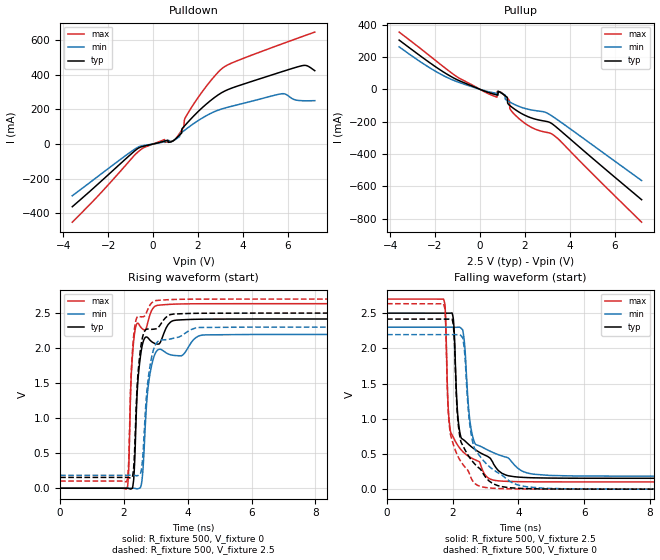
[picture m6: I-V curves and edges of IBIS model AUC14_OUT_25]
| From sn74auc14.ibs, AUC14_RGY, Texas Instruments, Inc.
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[Model]   AUC14_OUT_25
Model_type  Output
Vref =   0
Rref =   500
Cref =   30p
Vmeas =   1.25
| variable   typ   min   max
C_comp   8.27pF   2.05pF   24.54pF
| C_pullup   9.62pF   2.22pF   24.54pF
| C_pulldown   6.92pF   2.05pF   16.12pF
[Temperature Range]   40   100   -40
| Ambient temperature   25   85   -40
[Voltage range]   2.5   2.3   2.7
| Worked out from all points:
|   slope of the pulldown table from 0 to 0.375 V, typ, clamps not added: 30.7 ohm
|   slope of the pullup table from 0 to 0.375 V, typ, clamps not added: 19.1 ohm
|   rising waveform, R_fixture 500, V_fixture 0: 20-80 % time 188ps typ, 251ps min, 141ps max; typ from 0 V to 2.42 V
|   falling waveform, R_fixture 500, V_fixture 2.5: 20-80 % time 450ps typ, 462ps min, 354ps max; typ from 2.5 V to 0.155 V
|   rising waveform, R_fixture 500, V_fixture 2.5: 20-80 % time 191ps typ, 259ps min, 142ps max; typ from 0.154 V to 2.5 V
|   falling waveform, R_fixture 500, V_fixture 0: 20-80 % time 401ps typ, 485ps min, 301ps max; typ from 2.42 V to 0 V
[Pulldown]
| AUC14_OUT_25
|   Voltage   I(typ)   I(min)   I(max)
-3.6V     -363.3mA   -299.7mA   -452.8mA
-560mV    -17.97mA   -12.29mA   -33.51mA
510mV     17.07mA    12.84mA    25.87mA
975mV     26.82mA    25.47mA    25.82mA
1.27V     63.12mA    66.67mA    79.37mA
1.37V     100.7mA    76.6mA     99.34mA
1.42V     107.9mA    81.53mA    148.5mA
1.84V     166.6mA    121.2mA    238mA
3.1V      300.6mA    204.7mA    440.5mA
5.74V     418.9mA    291.2mA    579.9mA
6.745V    455.6mA    250.5mA    627.2mA
7.2V      424.9mA    251.1mA    648.3mA
[Pullup]
| AUC14_OUT_25
|   Voltage   I(typ)   I(min)   I(max)
-3.6V     305mA      263.2mA    354.5mA
-960mV    55.76mA    44.28mA    72.07mA
730mV     -33.82mA   -24.42mA   -47.21mA
760mV     -34.84mA   -25.13mA   -47.16mA
770mV     -35.18mA   -25.36mA   -13.25mA
980mV     -25.02mA   -24.81mA   -22.86mA
1.215V    -49.49mA   -69.56mA   -54.81mA
1.3V      -96.78mA   -76.45mA   -67.02mA
1.34V     -101.5mA   -79.57mA   -121.6mA
1.66V     -133.9mA   -101.4mA   -171.6mA
3.46V     -241mA     -189.3mA   -303.8mA
7.2V      -683.6mA   -565.1mA   -822.8mA
[Ramp]
| AUC14_OUT_25
| variable   typ   min   max
dV/dt_r   1.46/1.88E-10   1.32/2.51E-10   1.59/1.43E-10
dV/dt_f   1.41/4.50E-10   1.27/4.63E-10   1.56/3.59E-10
R_load = 500
[Rising Waveform]
| AUC14_OUT_25
R_fixture =   500
C_fixture =   0
L_fixture =   0
V_fixture =   0
V_fixture_min = 0
V_fixture_max = 0
|   Time   V(typ)   V(min)   V(max)
0s        13.01nV    39.01nV    2.017nV
2.085ns   260.6uV    462.9uV    -4.945mV
2.145ns   -3.048mV   695.5uV    232.7mV
2.235ns   -7.736mV   886.8uV    1.668V
2.345ns   486.5mV    -2.513mV   2.25V
2.43ns    1.488V     -7.472mV   2.356V
2.57ns    2.032V     134.6mV    2.279V
2.76ns    2.143V     1.456V     2.388V
3.045ns   2.057V     1.968V     2.61V
22ns      2.416V     2.195V     2.634V
[Falling Waveform]
| AUC14_OUT_25
R_fixture =   500
C_fixture =   0
L_fixture =   0
V_fixture =   2.5
V_fixture_min = 2.3
V_fixture_max = 2.7
|   Time   V(typ)   V(min)   V(max)
0s        2.5V       2.3V       2.7V
1.72ns    2.5V       2.3V       2.699V
1.865ns   2.499V     2.3V       1.135V
1.94ns    2.5V       2.3V       806.6mV
2.025ns   2.384V     2.299V     729.3mV
2.14ns    1.135V     2.299V     632mV
2.245ns   746.1mV    2.29V      564.7mV
2.615ns   585.3mV    733.4mV    431.8mV
3.215ns   385.9mV    523mV      131.6mV
22ns      154.5mV    184.4mV    102.7mV
[Rising Waveform]
| AUC14_OUT_25
R_fixture =   500
C_fixture =   0
L_fixture =   0
V_fixture =   2.5
V_fixture_min = 2.3
V_fixture_max = 2.7
|   Time   V(typ)   V(min)   V(max)
0s        154.5mV    184.4mV    102.6mV
2.08ns    154.8mV    184.7mV    94.72mV
2.145ns   151.9mV    185mV      348.9mV
2.265ns   161.2mV    184.9mV    1.946V
2.345ns   667mV      182.3mV    2.328V
2.425ns   1.541V     179.7mV    2.449V
2.555ns   2.095V     289.5mV    2.446V
2.74ns    2.272V     1.488V     2.545V
2.985ns   2.274V     2.046V     2.677V
22ns      2.5V       2.3V       2.7V
[Falling Waveform]
| AUC14_OUT_25
R_fixture =   500
C_fixture =   0
L_fixture =   0
V_fixture =   0
V_fixture_min = 0
V_fixture_max = 0
|   Time   V(typ)   V(min)   V(max)
0s        2.416V     2.195V     2.634V
1.72ns    2.416V     2.195V     2.632V
1.93ns    2.414V     2.195V     780.2mV
2.025ns   2.295V     2.195V     626.3mV
2.13ns    1.151V     2.194V     494.6mV
2.235ns   701.1mV    2.186V     401.9mV
2.565ns   416.2mV    770.5mV    152.3mV
2.875ns   263.4mV    439.3mV    34.57mV
4.75ns    3.284mV    13.71mV    801.9uV
22ns      52.05uV    19.62uV    23.46uV
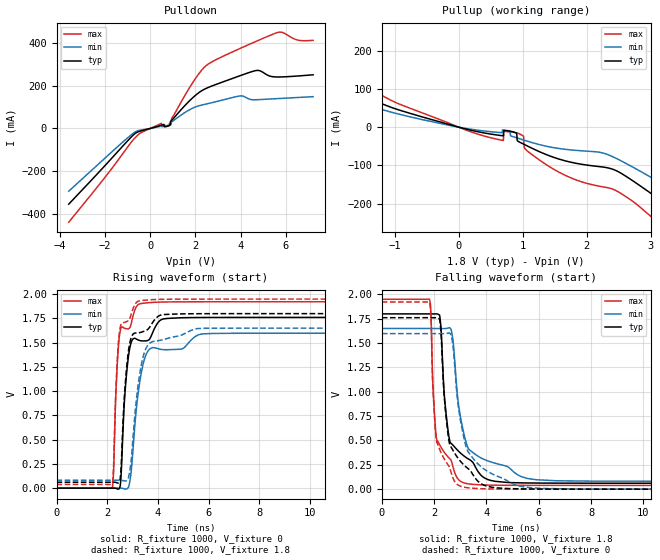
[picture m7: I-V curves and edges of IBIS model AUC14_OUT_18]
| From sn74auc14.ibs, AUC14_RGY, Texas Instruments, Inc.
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[Model]   AUC14_OUT_18
Model_type  Output
Vref =   0
Rref =   1000
Cref =   30p
Vmeas =   0.9
| variable   typ   min   max
C_comp   7.54pF   0.86pF   22.32pF
| C_pullup   8.40pF   1.40pF   22.32pF
| C_pulldown   6.69pF   0.86pF   15.74pF
[Temperature Range]   40   100   -40
| Ambient temperature   25   85   -40
[Voltage range]   1.8   1.65   1.95
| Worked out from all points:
|   slope of the pulldown table from 0 to 0.27 V, typ, clamps not added: 34.3 ohm
|   slope of the pullup table from 0 to 0.27 V, typ, clamps not added: 24.6 ohm
|   rising waveform, R_fixture 1000, V_fixture 0: 20-80 % time 281ps typ, 421ps min, 193ps max; typ from 0 V to 1.76 V
|   falling waveform, R_fixture 1000, V_fixture 1.8: 20-80 % time 565ps typ, 611ps min, 383ps max; typ from 1.8 V to 0.061 V
|   rising waveform, R_fixture 1000, V_fixture 1.8: 20-80 % time 279ps typ, 418ps min, 191ps max; typ from 0.061 V to 1.8 V
|   falling waveform, R_fixture 1000, V_fixture 0: 20-80 % time 527ps typ, 697ps min, 348ps max; typ from 1.76 V to 0 V
[Pulldown]
| AUC14_OUT_18
|   Voltage   I(typ)   I(min)   I(max)
-3.6V     -353mA     -292.5mA   -437.1mA
-555mV    -16.57mA   -11mA      -31.66mA
495mV     15.16mA    11.03mA    23.58mA
820mV     12.51mA    12.73mA    14.89mA
925mV     35.08mA    28.52mA    18.81mA
950mV     37.73mA    30.39mA    46.5mA
1.675V    122.4mA    83.44mA    179.3mA
2.51V     188.6mA    114.9mA    296mA
3.98V     246.3mA    151.7mA    373.5mA
4.685V    270.2mA    134mA      406.4mA
5.665V    240.1mA    139.5mA    448.4mA
7.2V      250.2mA    148.3mA    411mA
[Pullup]
| AUC14_OUT_18
|   Voltage   I(typ)   I(min)   I(max)
-3.6V     279.3mA    234.4mA    328.1mA
-2.85V    204.9mA    166.3mA    251mA
-1.38V    73.83mA    55.65mA    100.5mA
375mV     -14.45mA   -9.607mA   -22.05mA
940mV     -38.19mA   -29.59mA   -16.84mA
1.015V    -44.32mA   -33.6mA    -24.07mA
1.045V    -46.82mA   -35.18mA   -57.98mA
1.425V    -75.29mA   -51.77mA   -103.9mA
2.46V     -113.6mA   -81.44mA   -165.9mA
3.345V    -213mA     -163.7mA   -282.3mA
4.39V     -335.7mA   -266.5mA   -428.1mA
7.2V      -660.5mA   -545mA     -809.4mA
[Ramp]
| AUC14_OUT_18
| variable   typ   min   max
dV/dt_r   1.06/2.83E-10   0.97/4.25E-10   1.15/1.95E-10
dV/dt_f   1.04/5.66E-10   0.95/6.07E-10   1.15/3.84E-10
R_load = 1000
[Rising Waveform]
| AUC14_OUT_18
R_fixture =   1000
C_fixture =   0
L_fixture =   0
V_fixture =   0
V_fixture_min = 0
V_fixture_max = 0
|   Time   V(typ)   V(min)   V(max)
0s        10.21nV    35.63nV    1.217nV
2.205ns   682.8uV    301.2uV    5.141mV
2.365ns   -4.179mV   791.3uV    1.107V
2.495ns   6.33mV     1.135mV    1.593V
2.69ns    935.3mV    -7.569mV   1.648V
2.84ns    1.36V      8.339mV    1.644V
3.265ns   1.524V     1.061V     1.899V
3.68ns    1.54V      1.435V     1.913V
5.77ns    1.76V      1.591V     1.922V
22ns      1.761V     1.597V     1.922V
[Falling Waveform]
| AUC14_OUT_18
R_fixture =   1000
C_fixture =   0
L_fixture =   0
V_fixture =   1.8
V_fixture_min = 1.65
V_fixture_max = 1.95
|   Time   V(typ)   V(min)   V(max)
0s        1.8V       1.65V      1.95V
1.82ns    1.8V       1.65V      1.952V
1.965ns   1.8V       1.65V      1.001V
2.09ns    1.8V       1.65V      519.8mV
2.24ns    1.721V     1.649V     442.2mV
2.395ns   948.8mV    1.649V     376.3mV
2.58ns    517.7mV    1.658V     317.1mV
3.13ns    343.2mV    579.6mV    65.47mV
5.9ns     62.79mV    97.04mV    39.04mV
22ns      61.11mV    81.04mV    38.71mV
[Rising Waveform]
| AUC14_OUT_18
R_fixture =   1000
C_fixture =   0
L_fixture =   0
V_fixture =   1.8
V_fixture_min = 1.65
V_fixture_max = 1.95
|   Time   V(typ)   V(min)   V(max)
0s        61.05mV    81.01mV    38.68mV
2.205ns   61.7mV     81.28mV    45.57mV
2.25ns    61.61mV    81.39mV    208.2mV
2.365ns   57.4mV     81.71mV    1.143V
2.49ns    72.14mV    81.98mV    1.621V
2.83ns    1.396V     103.8mV    1.725V
3.225ns   1.601V     1.071V     1.928V
3.665ns   1.655V     1.491V     1.942V
5.555ns   1.799V     1.645V     1.95V
22ns      1.8V       1.65V      1.95V
[Falling Waveform]
| AUC14_OUT_18
R_fixture =   1000
C_fixture =   0
L_fixture =   0
V_fixture =   0
V_fixture_min = 0
V_fixture_max = 0
|   Time   V(typ)   V(min)   V(max)
0s        1.761V     1.597V     1.922V
1.82ns    1.761V     1.597V     1.923V
2.085ns   1.761V     1.597V     501.7mV
2.23ns    1.703V     1.597V     397.1mV
2.41ns    874.2mV    1.597V     300mV
2.65ns    431.5mV    1.581V     171.8mV
3.03ns    279.3mV    670.9mV    28.36mV
3.685ns   78.97mV    257.4mV    6.318mV
5.5ns     2.411mV    20.45mV    457.9uV
22ns      64.39uV    29.01uV    28.03uV
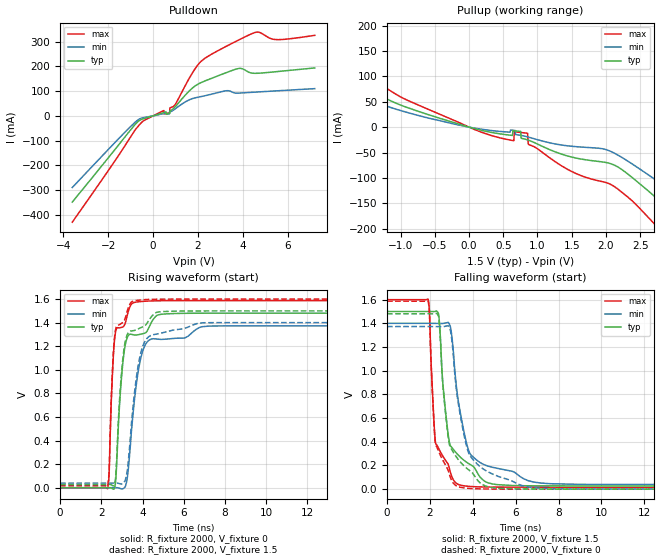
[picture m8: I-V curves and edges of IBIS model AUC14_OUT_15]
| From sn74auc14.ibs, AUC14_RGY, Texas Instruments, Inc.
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[Model]   AUC14_OUT_15
Model_type  Output
Vref =   0
Rref =   2000
Cref =   15p
Vmeas =   0.75
| variable   typ   min   max
C_comp   7.04pF   2.00pF   19.70pF
| C_pullup   7.01pF   2.00pF   19.70pF
| C_pulldown   7.08pF   4.51pF   15.46pF
[Temperature Range]   40   100   -40
| Ambient temperature   25   85   -40
[Voltage range]   1.5   1.4   1.6
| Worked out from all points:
|   slope of the pulldown table from 0 to 0.225 V, typ, clamps not added: 37.3 ohm
|   slope of the pullup table from 0 to 0.225 V, typ, clamps not added: 29.6 ohm
|   rising waveform, R_fixture 2000, V_fixture 0: 20-80 % time 365ps typ, 544ps min, 239ps max; typ from 0 V to 1.48 V
|   falling waveform, R_fixture 2000, V_fixture 1.5: 20-80 % time 648ps typ, 733ps min, 420ps max; typ from 1.5 V to 0.027 V
|   rising waveform, R_fixture 2000, V_fixture 1.5: 20-80 % time 360ps typ, 539ps min, 236ps max; typ from 0.027 V to 1.5 V
|   falling waveform, R_fixture 2000, V_fixture 0: 20-80 % time 635ps typ, 788ps min, 396ps max; typ from 1.48 V to 0 V
[Pulldown]
| AUC14_OUT_15
|   Voltage   I(typ)   I(min)   I(max)
-3.6V     -348.4mA   -289.5mA   -429.6mA
-665mV    -22.33mA   -15.81mA   -42.01mA
480mV     13.54mA    9.64mA     21.5mA
735mV     9.284mA    14.92mA    12.28mA
750mV     20.66mA    15.42mA    31.62mA
980mV     36.38mA    28.08mA    45.45mA
1.775V    114mA      70.34mA    177.1mA
2.235V    138.2mA    79.83mA    227.7mA
3.81V     191.5mA    91.9mA     306.5mA
4.58V     172mA      96.1mA     337.9mA
5.485V    178.5mA    101mA      308.2mA
7.2V      193.7mA    110mA      325.3mA
[Pullup]
| AUC14_OUT_15
|   Voltage   I(typ)   I(min)   I(max)
-3.6V     266mA      208.2mA    314.3mA
-2.885V   197.2mA    157.7mA    242.1mA
-2.5V     161mA      126.6mA    203.2mA
-900mV    38.43mA    28.74mA    52.85mA
390mV     -11.89mA   -7.641mA   -18.98mA
855mV     -25.04mA   -19.21mA   -12.06mA
870mV     -25.74mA   -19.76mA   -33.77mA
1.35V     -53.08mA   -35.2mA    -76.07mA
2.125V    -74.89mA   -51.34mA   -117.2mA
2.825V    -149.3mA   -113mA     -207mA
3.65V     -245.1mA   -192.4mA   -322.4mA
7.2V      -652.9mA   -541.5mA   -802.5mA
[Ramp]
| AUC14_OUT_15
| variable   typ   min   max
dV/dt_r   0.90/3.68E-10   0.83/5.48E-10   0.96/2.42E-10
dV/dt_f   0.89/6.44E-10   0.82/7.39E-10   0.95/4.20E-10
R_load = 2000
[Rising Waveform]
| AUC14_OUT_15
R_fixture =   2000
C_fixture =   0
L_fixture =   0
V_fixture =   0
V_fixture_min = 0
V_fixture_max = 0
|   Time   V(typ)   V(min)   V(max)
0s        9.392nV    35.9nV     957pV
2.305ns   661.8uV    250.1uV    -8.916mV
2.545ns   -8.991mV   931.7uV    995.7mV
2.665ns   18.2mV     1.167mV    1.294V
3.085ns   1.126V     -4.6mV     1.369V
3.275ns   1.281V     107.7mV    1.475V
3.565ns   1.296V     678.9mV    1.57V
4.22ns    1.329V     1.236V     1.583V
6.885ns   1.48V      1.365V     1.587V
22.3ns    1.481V     1.373V     1.587V
[Falling Waveform]
| AUC14_OUT_15
R_fixture =   2000
C_fixture =   0
L_fixture =   0
V_fixture =   1.5
V_fixture_min = 1.4
V_fixture_max = 1.6
|   Time   V(typ)   V(min)   V(max)
0s        1.5V       1.4V       1.6V
1.915ns   1.5V       1.4V       1.605V
2.265ns   1.502V     1.4V       389.9mV
2.415ns   1.464V     1.399V     340.9mV
2.62ns    858.6mV    1.399V     273.5mV
2.955ns   366.8mV    1.371V     141.5mV
3.355ns   281.5mV    711.6mV    37.76mV
3.935ns   202.2mV    284.7mV    22.26mV
6.83ns    28.43mV    60.45mV    16.65mV
22.3ns    27.25mV    38.8mV     16.43mV
[Rising Waveform]
| AUC14_OUT_15
R_fixture =   2000
C_fixture =   0
L_fixture =   0
V_fixture =   1.5
V_fixture_min = 1.4
V_fixture_max = 1.6
|   Time   V(typ)   V(min)   V(max)
0s        27.17mV    38.75mV    16.4mV
2.305ns   27.81mV    38.98mV    8.106mV
2.545ns   18.89mV    39.6mV     1.022V
2.66ns    48.88mV    39.8mV     1.308V
3.075ns   1.146V     41.06mV    1.409V
3.27ns    1.304V     164.9mV    1.506V
3.545ns   1.332V     704.8mV    1.584V
4.19ns    1.389V     1.262V     1.596V
6.68ns    1.499V     1.395V     1.6V
22.3ns    1.5V       1.4V       1.6V
[Falling Waveform]
| AUC14_OUT_15
R_fixture =   2000
C_fixture =   0
L_fixture =   0
V_fixture =   0
V_fixture_min = 0
V_fixture_max = 0
|   Time   V(typ)   V(min)   V(max)
0s        1.481V     1.373V     1.587V
1.915ns   1.48V      1.373V     1.591V
2.255ns   1.482V     1.372V     388.3mV
2.415ns   1.442V     1.372V     316.5mV
2.62ns    844.8mV    1.372V     238.2mV
2.955ns   351mV      1.34V      99.5mV
3.305ns   254.7mV    745.3mV    22.01mV
3.89ns    152.1mV    275.7mV    5.935mV
6.465ns   1.551mV    22.45mV    291.6uV
22.3ns    73.01uV    38.73uV    30.19uV
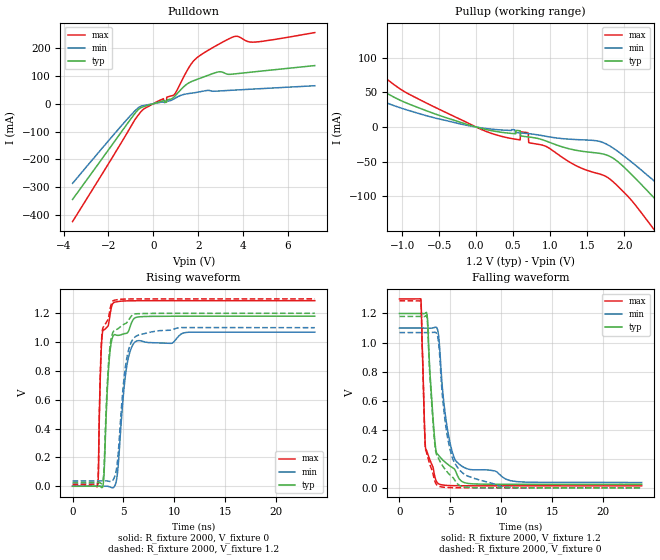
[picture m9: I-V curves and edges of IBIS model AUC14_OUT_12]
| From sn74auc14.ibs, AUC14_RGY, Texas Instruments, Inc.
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[Model]   AUC14_OUT_12
Model_type  Output
Vref =   0
Rref =   2000
Cref =   15p
Vmeas =   0.6
| variable   typ   min   max
C_comp   6.50pF   0.87pF   16.76pF
| C_pullup   6.25pF   0.87pF   16.76pF
| C_pulldown   6.74pF   4.64pF   15.17pF
[Temperature Range]   40   100   -40
| Ambient temperature   25   85   -40
[Voltage range]   1.2   1.1   1.3
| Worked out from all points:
|   slope of the pulldown table from 0 to 0.18 V, typ, clamps not added: 41.6 ohm
|   slope of the pullup table from 0 to 0.18 V, typ, clamps not added: 38.4 ohm
|   rising waveform, R_fixture 2000, V_fixture 0: 20-80 % time 517ps typ, 821ps min, 309ps max; typ from 0 V to 1.18 V
|   falling waveform, R_fixture 2000, V_fixture 1.2: 20-80 % time 712ps typ, 1.16ns min, 356ps max; typ from 1.2 V to 0.024 V
|   rising waveform, R_fixture 2000, V_fixture 1.2: 20-80 % time 508ps typ, 814ps min, 302ps max; typ from 0.024 V to 1.2 V
|   falling waveform, R_fixture 2000, V_fixture 0: 20-80 % time 742ps typ, 1.17ns min, 385ps max; typ from 1.18 V to 0 V
[Pulldown]
| AUC14_OUT_12
|   Voltage   I(typ)   I(min)   I(max)
-3.6V     -343.7mA   -285.9mA   -423.2mA
-650mV    -19.7mA    -13.52mA   -38.65mA
-370mV    -8.898mA   -5.454mA   -16.13mA
590mV     6.193mA    8.414mA    8.677mA
605mV     13.32mA    8.578mA    23.51mA
930mV     24.77mA    17.77mA    32.46mA
1.61V     76.08mA    36.87mA    132.9mA
1.985V    88.47mA    41.53mA    167.6mA
2.92V     114.6mA    45.74mA    213.7mA
3.635V    107.2mA    49.01mA    241.8mA
4.51V     114.7mA    52.9mA     221.3mA
7.2V      137mA      64.62mA    255.5mA
[Pullup]
| AUC14_OUT_12
|   Voltage   I(typ)   I(min)   I(max)
-3.6V     236.7mA    114.8mA    301.3mA
-2.45V    144.6mA    76.08mA    187.3mA
-2.055V   110.8mA    79.63mA    148.3mA
-675mV    23.63mA    16.44mA    34.85mA
270mV     -6.37mA    -3.622mA   -11.25mA
700mV     -14.19mA   -9.421mA   -8.122mA
715mV     -14.38mA   -9.579mA   -22.55mA
1.785V    -41.24mA   -25.95mA   -73.29mA
2.43V     -105mA     -79.97mA   -151.5mA
2.8V      -147.1mA   -114.5mA   -203.3mA
3.29V     -203.3mA   -161.3mA   -270.8mA
7.2V      -648.3mA   -542.2mA   -796.5mA
[Ramp]
| AUC14_OUT_12
| variable   typ   min   max
dV/dt_r   0.71/5.20E-10   0.65/8.27E-10   0.78/3.10E-10
dV/dt_f   0.71/7.16E-10   0.64/1.16E-09   0.77/3.58E-10
R_load = 2000
[Rising Waveform]
| AUC14_OUT_12
R_fixture =   2000
C_fixture =   0
L_fixture =   0
V_fixture =   0
V_fixture_min = 0
V_fixture_max = 0
|   Time   V(typ)   V(min)   V(max)
0s        8.805nV    38.15nV    771.5pV
2.495ns   653.9uV    168.2uV    16.57mV
2.75ns    -2.626mV   501.5uV    810.8mV
2.96ns    -5.224mV   708.5uV    1.074V
3.55ns    829.1mV    -1.849mV   1.129V
4.03ns    1.048V     -8.211mV   1.273V
4.425ns   1.047V     98.93mV    1.281V
5.28ns    1.061V     812.3mV    1.286V
6.165ns   1.17V      1.002V     1.287V
23.8ns    1.18V      1.069V     1.287V
[Falling Waveform]
| AUC14_OUT_12
R_fixture =   2000
C_fixture =   0
L_fixture =   0
V_fixture =   1.2
V_fixture_min = 1.1
V_fixture_max = 1.3
|   Time   V(typ)   V(min)   V(max)
0s        1.2V       1.1V       1.3V
2.11ns    1.2V       1.1V       1.301V
2.555ns   1.203V     1.099V     280.3mV
2.755ns   1.165V     1.099V     239.8mV
2.995ns   794.9mV    1.098V     192.1mV
3.45ns    346.5mV    1.104V     86.85mV
3.785ns   229.3mV    1.076V     31.16mV
4.73ns    163.2mV    398mV      16.43mV
6.035ns   49.38mV    154.2mV    14.4mV
23.8ns    24.06mV    36.69mV    13.89mV
[Rising Waveform]
| AUC14_OUT_12
R_fixture =   2000
C_fixture =   0
L_fixture =   0
V_fixture =   1.2
V_fixture_min = 1.1
V_fixture_max = 1.3
|   Time   V(typ)   V(min)   V(max)
0s        23.98mV    36.61mV    13.86mV
2.455ns   24.48mV    36.71mV    21.18mV
2.885ns   18.54mV    37.11mV    1.05V
3.075ns   105.7mV    37.16mV    1.11V
3.55ns    868.6mV    34.74mV    1.176V
3.985ns   1.071V     43.16mV    1.287V
4.4ns     1.091V     164.6mV    1.294V
5.245ns   1.13V      854.3mV    1.299V
6.175ns   1.196V     1.038V     1.3V
23.8ns    1.2V       1.1V       1.3V
[Falling Waveform]
| AUC14_OUT_12
R_fixture =   2000
C_fixture =   0
L_fixture =   0
V_fixture =   0
V_fixture_min = 0
V_fixture_max = 0
|   Time   V(typ)   V(min)   V(max)
0s        1.18V      1.069V     1.287V
2.11ns    1.18V      1.069V     1.287V
2.55ns    1.182V     1.069V     271mV
2.755ns   1.14V      1.068V     218.5mV
2.99ns    772.9mV    1.068V     161.2mV
3.41ns    350.3mV    1.07V      62.95mV
3.74ns    217.5mV    1.047V     16.3mV
4.78ns    102.3mV    327.5mV    2.145mV
6.28ns    7.793mV    98.3mV     426.1uV
23.8ns    82.21uV    63.56uV    30.71uV
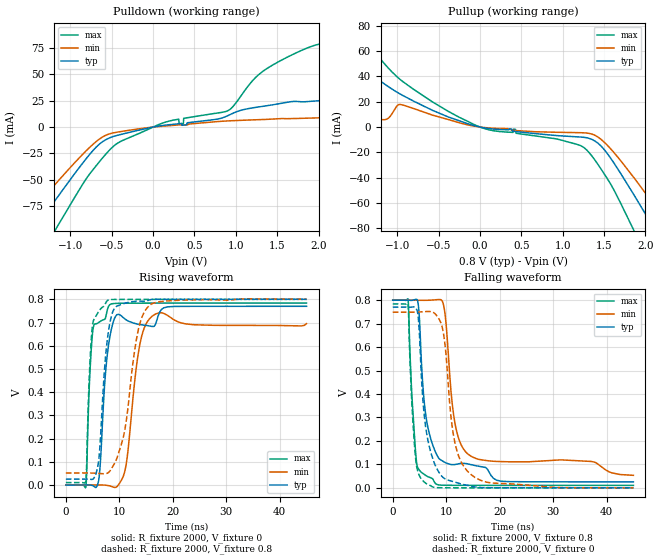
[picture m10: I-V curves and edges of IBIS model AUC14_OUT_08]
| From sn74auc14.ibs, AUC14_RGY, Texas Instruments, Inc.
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[Model]   AUC14_OUT_08
Model_type  Output
Vref =   0
Rref =   2000
Cref =   15p
Vmeas =   0.4
| variable   typ   min   max
C_comp   6.02pF   2.30pF   8.11pF
| C_pullup   5.60pF   2.30pF   8.11pF
| C_pulldown   6.44pF   5.86pF   6.78pF
[Temperature Range]   40   100   -40
| Ambient temperature   25   85   -40
[Voltage range]   0.8   0.8   0.8
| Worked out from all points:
|   slope of the pulldown table from 0 to 0.12 V, typ, clamps not added: 76.3 ohm
|   slope of the pullup table from 0 to 0.12 V, typ, clamps not added: 91.4 ohm
|   rising waveform, R_fixture 2000, V_fixture 0: 20-80 % time 1.47ns typ, 1.9ns min, 874ps max; typ from 0 V to 0.77 V
|   falling waveform, R_fixture 2000, V_fixture 0.8: 20-80 % time 2.36ns typ, 2.3ns min, 1.1ns max; typ from 0.8 V to 0.026 V
|   rising waveform, R_fixture 2000, V_fixture 0.8: 20-80 % time 1.46ns typ, 2.69ns min, 818ps max; typ from 0.025 V to 0.8 V
|   falling waveform, R_fixture 2000, V_fixture 0: 20-80 % time 2.01ns typ, 2.29ns min, 1.06ns max; typ from 0.77 V to 0 V
[Pulldown]
| AUC14_OUT_08
|   Voltage   I(typ)   I(min)   I(max)
-3.6V     -337.3mA   -282.2mA   -412.4mA
-1.79V    -136.5mA   -110mA     -177.8mA
-1.39V    -92.23mA   -73.02mA   -125.2mA
-1.17V    -68.14mA   -53.2mA    -96.14mA
-685mV    -18.8mA    -13.58mA   -36.41mA
-430mV    -7.788mA   -4.787mA   -15.34mA
165mV     1.975mA    1.123mA    5.083mA
905mV     10.9mA     5.849mA    15.59mA
1.32V     19.64mA    7.147mA    52.55mA
2.005V    25.03mA    8.767mA    78.7mA
3.335V    32.94mA    11.65mA    90.33mA
7.2V      56.65mA    21.1mA     140.7mA
[Pullup]
| AUC14_OUT_08
|   Voltage   I(typ)   I(min)   I(max)
-3.6V     112.9mA    15.55mA    196mA
-2.685V   76.06mA    17.84mA    164mA
-1.875V   36.81mA    19.48mA    111.1mA
-1.505V   32.64mA    11.52mA    78.71mA
-1.285V   39.44mA    7.211mA    60.37mA
-960mV    25.93mA    17.8mA     37.34mA
-245mV    4.855mA    3.296mA    7.535mA
1.26V     -8.135mA   -4.57mA    -16.37mA
1.87V     -54.47mA   -40.74mA   -82.92mA
2.04V     -72.97mA   -55.67mA   -106mA
2.465V    -120.2mA   -94.46mA   -163.4mA
7.2V      -650.8mA   -549.9mA   -789.4mA
[Ramp]
| AUC14_OUT_08
| variable   typ   min   max
dV/dt_r   0.47/1.47E-09   0.45/2.15E-09   0.48/8.77E-10
dV/dt_f   0.47/2.35E-09   0.45/2.29E-09   0.48/1.11E-09
R_load = 2000
[Rising Waveform]
| AUC14_OUT_08
R_fixture =   2000
C_fixture =   0
L_fixture =   0
V_fixture =   0
V_fixture_min = 0
V_fixture_max = 0
|   Time   V(typ)   V(min)   V(max)
0s        10.85nV    62.38nV    582.1pV
3.755ns   333uV      120.2uV    -8.773mV
4.345ns   258.6uV    255.6uV    404.2mV
4.855ns   -1.3mV     343uV      619.3mV
6.015ns   6.818mV    318.4uV    698.1mV
8.23ns    639mV      -3.889mV   777.3mV
10.99ns   716.3mV    56.47mV    783.2mV
13.69ns   692mV      588.3mV    783.5mV
16.09ns   683.2mV    726.4mV    783.6mV
45ns      770mV      695.2mV    783.7mV
[Falling Waveform]
| AUC14_OUT_08
R_fixture =   2000
C_fixture =   0
L_fixture =   0
V_fixture =   0.8
V_fixture_min = 0.8
V_fixture_max = 0.8
|   Time   V(typ)   V(min)   V(max)
0s        800mV      800mV      800mV
2.855ns   799.5mV    800mV      804.8mV
3.615ns   799mV      799.7mV    381.1mV
4.655ns   797.4mV    799.4mV    87.63mV
6.045ns   333.2mV    799.1mV    55.06mV
8.075ns   148.7mV    801.5mV    16.55mV
9.56ns    110.9mV    773.1mV    11.22mV
11.51ns   99.1mV     292.2mV    10.83mV
13.99ns   102.4mV    145.3mV    10.73mV
45ns      25.56mV    53.43mV    10.62mV
[Rising Waveform]
| AUC14_OUT_08
R_fixture =   2000
C_fixture =   0
L_fixture =   0
V_fixture =   0.8
V_fixture_min = 0.8
V_fixture_max = 0.8
|   Time   V(typ)   V(min)   V(max)
0s        25.46mV    51.93mV    10.6mV
3.75ns    25.46mV    51.92mV    20.37mV
4.7ns     24.34mV    51.67mV    609.5mV
5.665ns   50.41mV    50.68mV    729.3mV
6.26ns    134.3mV    49.76mV    751.5mV
7.81ns    636.3mV    51.7mV     795.5mV
10.71ns   780.4mV    203.1mV    799.6mV
13.39ns   792.2mV    650.9mV    799.8mV
15.59ns   796.9mV    772.5mV    799.8mV
45ns      799.9mV    800.2mV    800mV
[Falling Waveform]
| AUC14_OUT_08
R_fixture =   2000
C_fixture =   0
L_fixture =   0
V_fixture =   0
V_fixture_min = 0
V_fixture_max = 0
|   Time   V(typ)   V(min)   V(max)
0s        770mV      748.6mV    783.8mV
2.855ns   769.7mV    748.5mV    783mV
3.625ns   770.5mV    748.6mV    339mV
4.58ns    753.9mV    749mV      80.45mV
5.6ns     387.3mV    750.2mV    31.57mV
6.155ns   260mV      751.1mV    20.11mV
9.2ns     49.15mV    689.4mV    431.6uV
11.49ns   25.58mV    207.1mV    190.9uV
14.49ns   8.476mV    59.37mV    111.7uV
45ns      72.02uV    54.53uV    20.46uV
